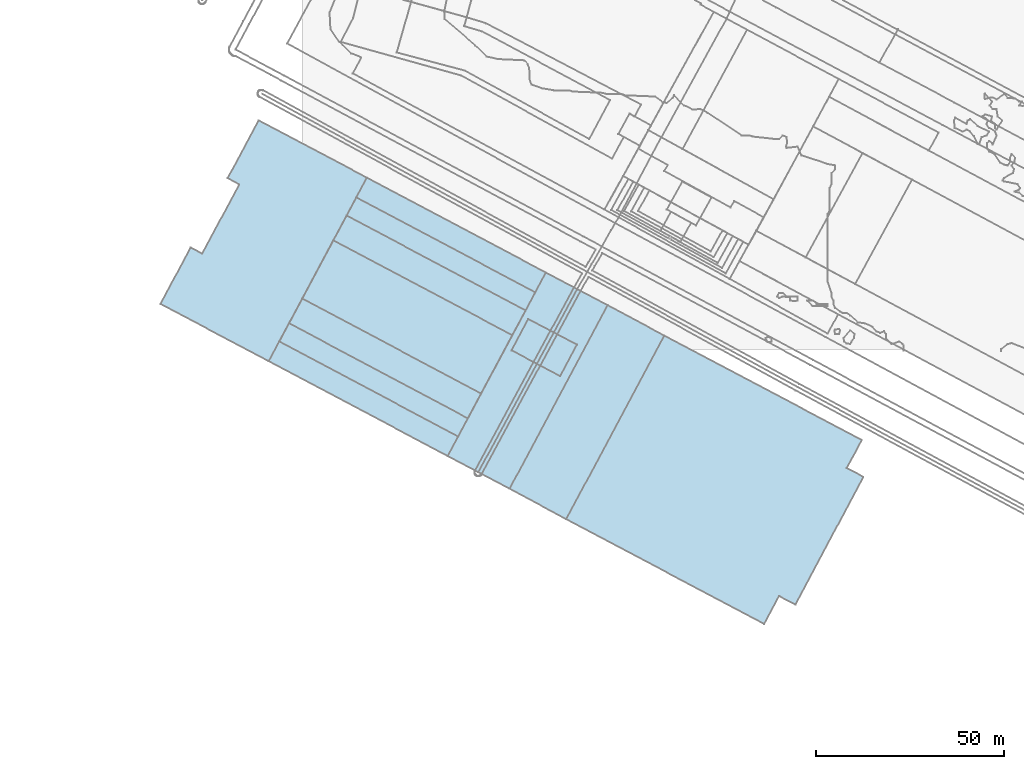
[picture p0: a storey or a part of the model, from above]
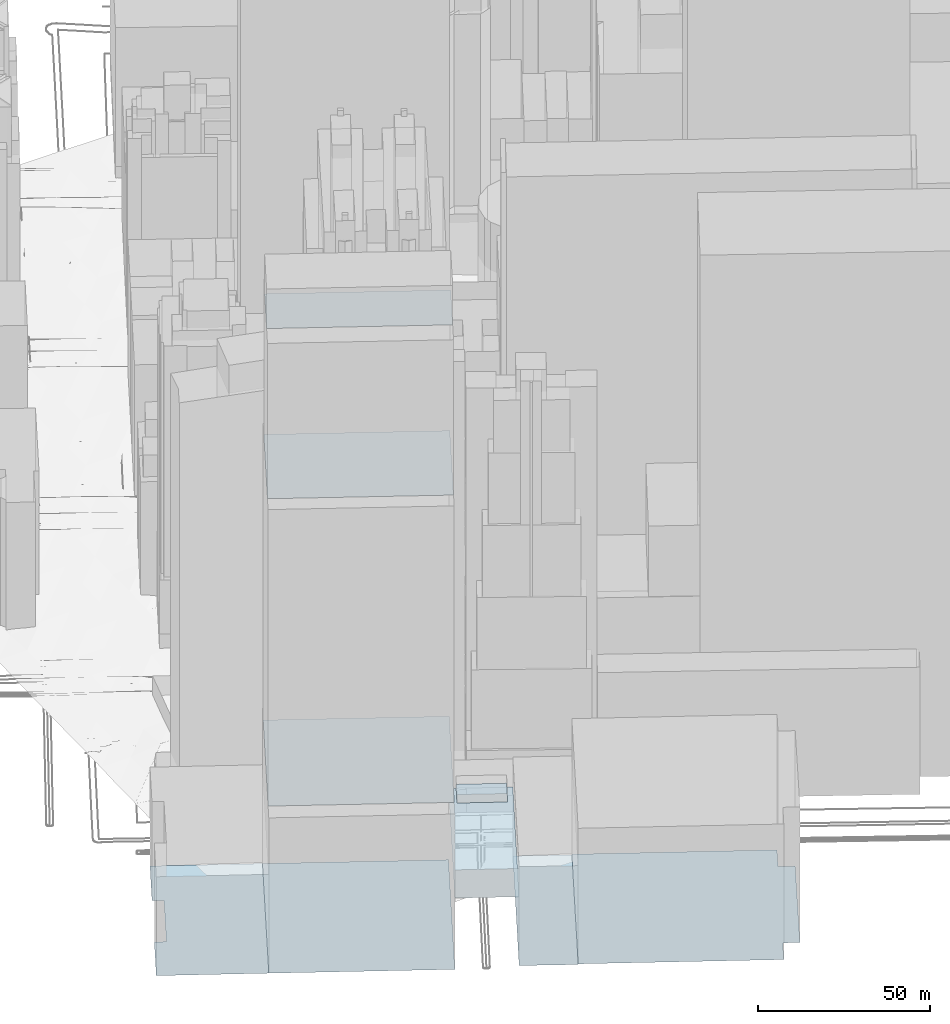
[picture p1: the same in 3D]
Properties of the parts of a building model (IFC4)

# File
Description: ViewDefinition [CoordinationView]
Time: 2024-08-21T15:29:07
Written by: TpxIfclib v0.1
Made in: TpxIfclib v0.1

# IfcGeographicElement (38)
Name | In
TPX_SOL | TPX_SOL | PredefinedType: TERRAIN
Contour 25.0 m | TPX_CONTOURS
36 x Contour 20.0 m | TPX_CONTOURS

# IfcGeographicElement: VEGETATION (10)
In: TPX_ARBRES
PredefinedType: USERDEFINED
